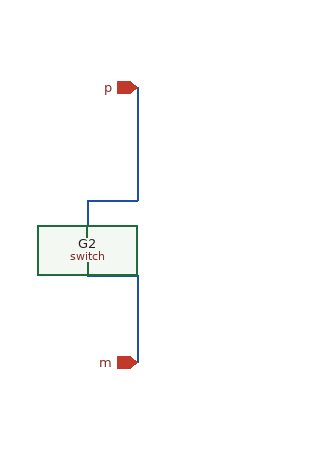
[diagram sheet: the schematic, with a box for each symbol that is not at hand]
v {xschem version=2.9.5_RC5 file_version=1.1}
G {}
V {}
S {}
E {}
N 110 -90 110 -20 {lab=m}
N 110 -240 110 -150 {lab=p}
N 70 -150 70 -120 {}
N 70 -150 110 -150 {}
N 70 -100 70 -90 {}
N 70 -90 110 -90 {}
C {iopin.sym} 110 -240 0 0 {name=p0 lab=p}
C {iopin.sym} 110 -20 0 0 {name=p1 lab=m}
C {switch.sym} 110 -120 0 0 {name=G2 TABLE="'VTH-0.1' ROFF 'VTH+0.1' RON"}
